VERSION 5.7 ;
  NOWIREEXTENSIONATPIN ON ;
  DIVIDERCHAR "/" ;
  BUSBITCHARS "[]" ;
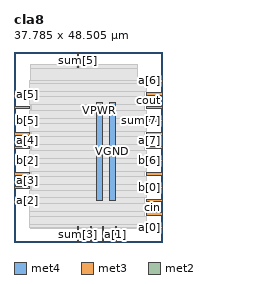
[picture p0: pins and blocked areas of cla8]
MACRO cla8
  CLASS BLOCK ;
  FOREIGN cla8 ;
  ORIGIN 0.000 0.000 ;
  SIZE 37.785 BY 48.505 ;
  PIN VGND
    DIRECTION INOUT ;
    USE GROUND ;
    PORT
      LAYER met4 ;
        RECT 24.340 10.640 25.940 35.600 ;
    END
  END VGND
  PIN VPWR
    DIRECTION INOUT ;
    USE POWER ;
    PORT
      LAYER met4 ;
        RECT 21.040 10.640 22.640 35.600 ;
    END
  END VPWR
  PIN a[0]
    DIRECTION INPUT ;
    USE SIGNAL ;
    ANTENNAGATEAREA 0.196500 ;
    PORT
      LAYER met3 ;
        RECT 33.785 3.440 37.785 4.040 ;
    END
  END a[0]
  PIN a[1]
    DIRECTION INPUT ;
    USE SIGNAL ;
    ANTENNAGATEAREA 0.196500 ;
    PORT
      LAYER met2 ;
        RECT 25.850 0.000 26.130 4.000 ;
    END
  END a[1]
  PIN a[2]
    DIRECTION INPUT ;
    USE SIGNAL ;
    ANTENNAGATEAREA 0.196500 ;
    PORT
      LAYER met3 ;
        RECT 0.000 10.240 4.000 10.840 ;
    END
  END a[2]
  PIN a[3]
    DIRECTION INPUT ;
    USE SIGNAL ;
    ANTENNAGATEAREA 0.196500 ;
    PORT
      LAYER met3 ;
        RECT 0.000 13.640 4.000 14.240 ;
    END
  END a[3]
  PIN a[4]
    DIRECTION INPUT ;
    USE SIGNAL ;
    ANTENNAGATEAREA 0.196500 ;
    PORT
      LAYER met3 ;
        RECT 0.000 23.840 4.000 24.440 ;
    END
  END a[4]
  PIN a[5]
    DIRECTION INPUT ;
    USE SIGNAL ;
    ANTENNAGATEAREA 0.196500 ;
    PORT
      LAYER met3 ;
        RECT 0.000 37.440 4.000 38.040 ;
    END
  END a[5]
  PIN a[6]
    DIRECTION INPUT ;
    USE SIGNAL ;
    ANTENNAGATEAREA 0.196500 ;
    PORT
      LAYER met3 ;
        RECT 33.785 40.840 37.785 41.440 ;
    END
  END a[6]
  PIN a[7]
    DIRECTION INPUT ;
    USE SIGNAL ;
    ANTENNAGATEAREA 0.196500 ;
    PORT
      LAYER met3 ;
        RECT 33.785 23.840 37.785 24.440 ;
    END
  END a[7]
  PIN b[0]
    DIRECTION INPUT ;
    USE SIGNAL ;
    ANTENNAGATEAREA 0.196500 ;
    PORT
      LAYER met3 ;
        RECT 33.785 13.640 37.785 14.240 ;
    END
  END b[0]
  PIN b[1]
    DIRECTION INPUT ;
    USE SIGNAL ;
    ANTENNAGATEAREA 0.196500 ;
    PORT
      LAYER met2 ;
        RECT 22.630 0.000 22.910 4.000 ;
    END
  END b[1]
  PIN b[2]
    DIRECTION INPUT ;
    USE SIGNAL ;
    ANTENNAGATEAREA 0.196500 ;
    PORT
      LAYER met3 ;
        RECT 0.000 20.440 4.000 21.040 ;
    END
  END b[2]
  PIN b[3]
    DIRECTION INPUT ;
    USE SIGNAL ;
    ANTENNAGATEAREA 0.196500 ;
    PORT
      LAYER met3 ;
        RECT 0.000 17.040 4.000 17.640 ;
    END
  END b[3]
  PIN b[4]
    DIRECTION INPUT ;
    USE SIGNAL ;
    ANTENNAGATEAREA 0.196500 ;
    PORT
      LAYER met3 ;
        RECT 0.000 27.240 4.000 27.840 ;
    END
  END b[4]
  PIN b[5]
    DIRECTION INPUT ;
    USE SIGNAL ;
    ANTENNAGATEAREA 0.196500 ;
    PORT
      LAYER met3 ;
        RECT 0.000 30.640 4.000 31.240 ;
    END
  END b[5]
  PIN b[6]
    DIRECTION INPUT ;
    USE SIGNAL ;
    ANTENNAGATEAREA 0.196500 ;
    PORT
      LAYER met3 ;
        RECT 33.785 20.440 37.785 21.040 ;
    END
  END b[6]
  PIN b[7]
    DIRECTION INPUT ;
    USE SIGNAL ;
    ANTENNAGATEAREA 0.196500 ;
    PORT
      LAYER met3 ;
        RECT 33.785 27.240 37.785 27.840 ;
    END
  END b[7]
  PIN cin
    DIRECTION INPUT ;
    USE SIGNAL ;
    ANTENNAGATEAREA 0.196500 ;
    PORT
      LAYER met3 ;
        RECT 33.785 10.240 37.785 10.840 ;
    END
  END cin
  PIN cout
    DIRECTION OUTPUT ;
    USE SIGNAL ;
    ANTENNADIFFAREA 0.445500 ;
    PORT
      LAYER met3 ;
        RECT 33.785 37.440 37.785 38.040 ;
    END
  END cout
  PIN sum[0]
    DIRECTION OUTPUT ;
    USE SIGNAL ;
    ANTENNADIFFAREA 0.445500 ;
    PORT
      LAYER met3 ;
        RECT 33.785 6.840 37.785 7.440 ;
    END
  END sum[0]
  PIN sum[1]
    DIRECTION OUTPUT ;
    USE SIGNAL ;
    ANTENNADIFFAREA 0.445500 ;
    PORT
      LAYER met3 ;
        RECT 33.785 17.040 37.785 17.640 ;
    END
  END sum[1]
  PIN sum[2]
    DIRECTION OUTPUT ;
    USE SIGNAL ;
    ANTENNADIFFAREA 0.445500 ;
    PORT
      LAYER met2 ;
        RECT 19.410 0.000 19.690 4.000 ;
    END
  END sum[2]
  PIN sum[3]
    DIRECTION OUTPUT ;
    USE SIGNAL ;
    ANTENNADIFFAREA 0.445500 ;
    PORT
      LAYER met2 ;
        RECT 16.190 0.000 16.470 4.000 ;
    END
  END sum[3]
  PIN sum[4]
    DIRECTION OUTPUT ;
    USE SIGNAL ;
    ANTENNADIFFAREA 0.445500 ;
    PORT
      LAYER met3 ;
        RECT 0.000 34.040 4.000 34.640 ;
    END
  END sum[4]
  PIN sum[5]
    DIRECTION OUTPUT ;
    USE SIGNAL ;
    ANTENNADIFFAREA 0.445500 ;
    PORT
      LAYER met2 ;
        RECT 16.190 44.505 16.470 48.505 ;
    END
  END sum[5]
  PIN sum[6]
    DIRECTION OUTPUT ;
    USE SIGNAL ;
    ANTENNADIFFAREA 0.445500 ;
    PORT
      LAYER met3 ;
        RECT 33.785 34.040 37.785 34.640 ;
    END
  END sum[6]
  PIN sum[7]
    DIRECTION OUTPUT ;
    USE SIGNAL ;
    ANTENNADIFFAREA 0.445500 ;
    PORT
      LAYER met3 ;
        RECT 33.785 30.640 37.785 31.240 ;
    END
  END sum[7]
  OBS
      LAYER nwell ;
        RECT 5.330 10.795 32.390 35.550 ;
      LAYER li1 ;
        RECT 5.520 10.795 32.200 35.445 ;
      LAYER met1 ;
        RECT 4.210 10.640 32.200 35.600 ;
      LAYER met2 ;
        RECT 4.230 44.225 15.910 45.290 ;
        RECT 16.750 44.225 31.650 45.290 ;
        RECT 4.230 4.280 31.650 44.225 ;
        RECT 4.230 3.555 15.910 4.280 ;
        RECT 16.750 3.555 19.130 4.280 ;
        RECT 19.970 3.555 22.350 4.280 ;
        RECT 23.190 3.555 25.570 4.280 ;
        RECT 26.410 3.555 31.650 4.280 ;
      LAYER met3 ;
        RECT 3.990 40.440 33.385 41.305 ;
        RECT 3.990 38.440 33.785 40.440 ;
        RECT 4.400 37.040 33.385 38.440 ;
        RECT 3.990 35.040 33.785 37.040 ;
        RECT 4.400 33.640 33.385 35.040 ;
        RECT 3.990 31.640 33.785 33.640 ;
        RECT 4.400 30.240 33.385 31.640 ;
        RECT 3.990 28.240 33.785 30.240 ;
        RECT 4.400 26.840 33.385 28.240 ;
        RECT 3.990 24.840 33.785 26.840 ;
        RECT 4.400 23.440 33.385 24.840 ;
        RECT 3.990 21.440 33.785 23.440 ;
        RECT 4.400 20.040 33.385 21.440 ;
        RECT 3.990 18.040 33.785 20.040 ;
        RECT 4.400 16.640 33.385 18.040 ;
        RECT 3.990 14.640 33.785 16.640 ;
        RECT 4.400 13.240 33.385 14.640 ;
        RECT 3.990 11.240 33.785 13.240 ;
        RECT 4.400 9.840 33.385 11.240 ;
        RECT 3.990 7.840 33.785 9.840 ;
        RECT 3.990 6.440 33.385 7.840 ;
        RECT 3.990 4.440 33.785 6.440 ;
        RECT 3.990 3.575 33.385 4.440 ;
  END
END cla8
END LIBRARY

